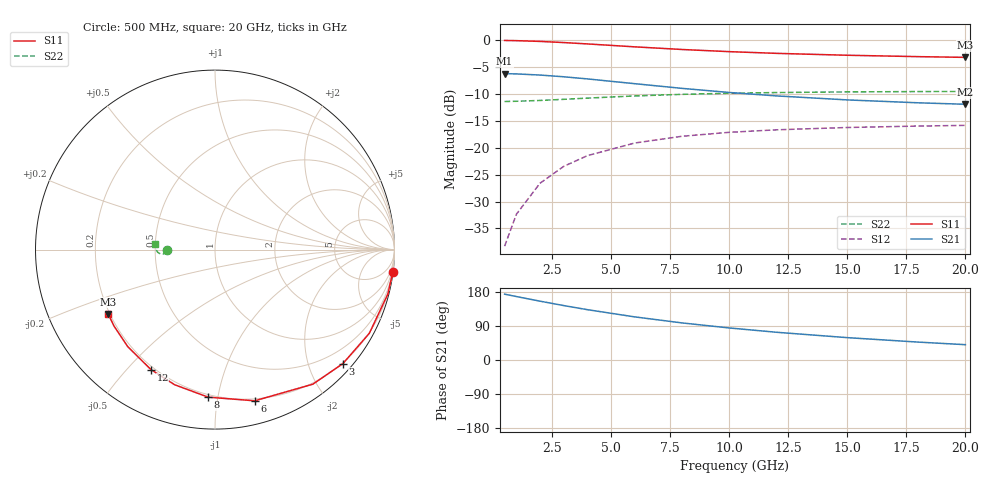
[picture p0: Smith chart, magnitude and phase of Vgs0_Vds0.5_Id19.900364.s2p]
# Hz S RI R 50
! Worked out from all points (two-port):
!   12 points, 500 MHz to 20 GHz, reference 50 ohm
!   highest |S21| = -6.19 dB at 500 MHz (marker M1); lowest = -11.9 dB at 20 GHz (marker M2)
!   |S21| within 3 dB of the highest: start of sweep to 8.681 GHz
!   lowest |S11| = -3.2 dB at 20 GHz (marker M3), VSWR 5.56, Z = 9.67 - j13.4 ohm
!   |S11| at or under -10 dB: nowhere
!   |S22| runs from -11.4 to -9.5 dB; largest |S21 - S12| = 0.49
!   S11 on the Smith chart (normalised r, x): 500 MHz: 0, -16; 3 GHz: 0.18, -2.61; 6 GHz: 0.18, -1.28; 8 GHz: 0.18, -0.94; 12 GHz: 0.19, -0.58; 20 GHz: 0.19, -0.27
5e8  0.9906 -0.1259  -0.4876 0.0538  0.000965 0.0121  -0.27 -0.00444
1e9  0.9629 -0.2479  -0.4758 0.106  0.0038 0.0238  -0.2712 -0.0087
2e9  0.86 -0.466  -0.4321 0.1993  0.0143 0.0446  -0.2757 -0.0161
3e9  0.7128 -0.635  -0.3694 0.2718  0.0294 0.0604  -0.2821 -0.0213
4e9  0.5452 -0.7498  -0.298 0.3212  0.0465 0.0706  -0.2893 -0.0242
6e9  0.221 -0.8425  -0.1598 0.3619  0.0797 0.077  -0.3032 -0.024
8e9  -0.0379 -0.8222  -0.0493 0.3545  0.1061 0.0718  -0.3141 -0.0188
1e10  -0.2252 -0.7528  0.031 0.3262  0.1252 0.0616  -0.3219 -0.0113
1.2e10  -0.3572 -0.668  0.0879 0.2915  0.1385 0.0498  -0.3271 -0.00298
1.5e10  -0.4856 -0.5413  0.1439 0.2395  0.1513 0.0321  -0.3315 0.00967
1.8e10  -0.5621 -0.4272  0.1782 0.1928  0.1587 0.0156  -0.3333 0.0221
2e10  -0.5951 -0.359  0.1937 0.165  0.1618 0.00546  -0.3334 0.0303
